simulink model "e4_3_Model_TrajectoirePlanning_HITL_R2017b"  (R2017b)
settings: Solver=FixedStepAuto  StartTime=0.0  StopTime=inf  FixedStep=sampleTime  RelTol=1e-3  EnableMultiTasking=on
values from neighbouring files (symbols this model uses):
  k2_d_x = 1/2    (= 0.5)    [e4_3_Model_TrajectoirePlanning_code.m]    (also in e4_1_Model_TrajectoirePlanning_HITL_code.m; e4_1_TF_TrajectoirePlanning_code.m = 1; e4_1_Model_TrajectoirePlanning_code.m; e4_2_TF_TrajectoirePlanning_code.m = 1)
  k2_d_y = 1/2.65    (= 0.377358490566)    [e4_3_Model_TrajectoirePlanning_code.m]    (also in e4_1_Model_TrajectoirePlanning_HITL_code.m; e4_1_TF_TrajectoirePlanning_code.m = 1; e4_1_Model_TrajectoirePlanning_code.m; e4_2_TF_TrajectoirePlanning_code.m = 1)
  k2_d_z = 10    [e4_3_Model_TrajectoirePlanning_code.m]    (also in e4_1_Model_TrajectoirePlanning_HITL_code.m; e4_1_TF_TrajectoirePlanning_code.m; e4_1_Model_TrajectoirePlanning_code.m; e4_2_TF_TrajectoirePlanning_code.m)
  k2_p_x = 1/1.55    (= 0.645161290323)    [e4_3_Model_TrajectoirePlanning_code.m]    (also in e4_1_Model_TrajectoirePlanning_HITL_code.m; e4_1_TF_TrajectoirePlanning_code.m = 1.25; e4_1_Model_TrajectoirePlanning_code.m; e4_2_TF_TrajectoirePlanning_code.m = 1.25)
  k2_p_y = 1/2.5    (= 0.4)    [e4_3_Model_TrajectoirePlanning_code.m]    (also in e4_1_Model_TrajectoirePlanning_HITL_code.m; e4_1_TF_TrajectoirePlanning_code.m = 1.25; e4_1_Model_TrajectoirePlanning_code.m; e4_2_TF_TrajectoirePlanning_code.m = 1.25)
  k2_p_yaw = 1.6    [e4_3_Model_TrajectoirePlanning_code.m]    (also in e4_1_Model_TrajectoirePlanning_HITL_code.m; e4_1_TF_TrajectoirePlanning_code.m; e4_1_Model_TrajectoirePlanning_code.m; e4_2_TF_TrajectoirePlanning_code.m)
  k2_p_z = 1    [e4_3_Model_TrajectoirePlanning_code.m]    (also in e4_1_Model_TrajectoirePlanning_HITL_code.m; e4_1_TF_TrajectoirePlanning_code.m; e4_1_Model_TrajectoirePlanning_code.m; e4_2_TF_TrajectoirePlanning_code.m)
  sampleTime = 0.01    [startSimulation.m]    (also in start.m)
  saturation_psi = 2    [startSimulation.m]    (also in start.m)
  saturation_x = 2    [startSimulation.m]    (also in start.m)
  saturation_y = 2    [startSimulation.m]    (also in start.m)
  saturation_z = 2    [startSimulation.m]    (also in start.m)
libraries: simulink x3, etargetslib x2, aerolibanimutils x1

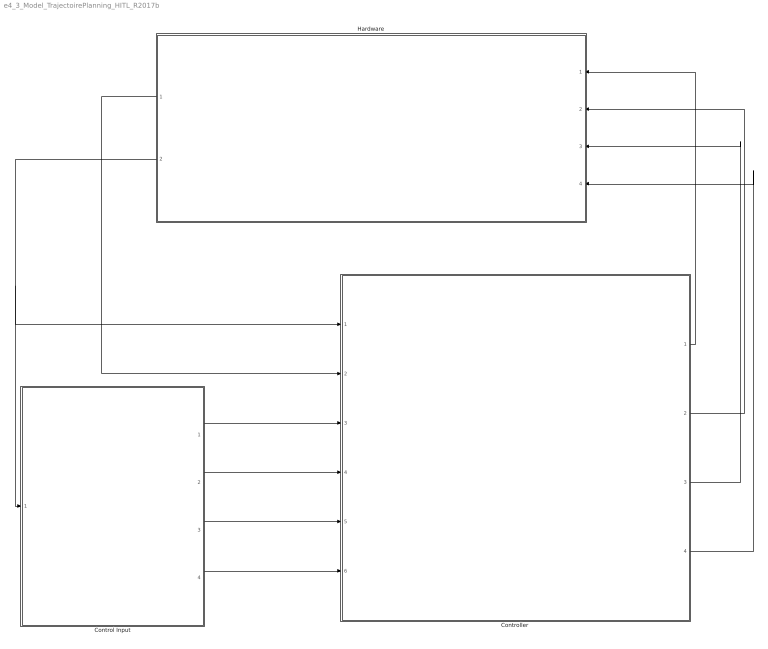
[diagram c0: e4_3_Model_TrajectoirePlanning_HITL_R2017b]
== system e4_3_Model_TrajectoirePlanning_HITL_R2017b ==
  Control Input : Subsystem
  "Controller " : Subsystem
  Hardware : Subsystem
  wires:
  Control Input/1(ux) -> "Controller "/3(Control input X)
  Control Input/2(uy) -> "Controller "/4(Control input Y)
  Control Input/3(uz) -> "Controller "/5(Control input H)
  Control Input/4(upsi) -> "Controller "/6(Control input Psi)
  "Controller "/1(Controller Output X) -> Hardware/1(X)
  "Controller "/2(Controller Output Y) -> Hardware/2(Y)
  "Controller "/3(Controller Output H) -> Hardware/3(H)
  "Controller "/4(Controller Output Psi) -> Hardware/4(Psi)
  Hardware/1(Vel) -> "Controller "/2(Feedback Velocity)
  Hardware/2(Pos) -> "Controller "/1(Feedback Position), Control Input/1(Position Feedback)

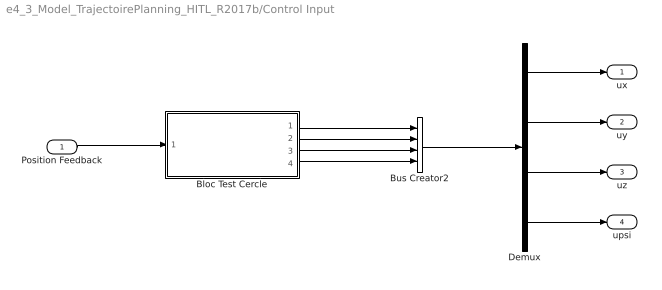
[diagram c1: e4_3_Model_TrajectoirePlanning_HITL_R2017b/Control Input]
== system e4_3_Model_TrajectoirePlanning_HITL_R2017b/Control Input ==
  Position Feedback : Inport
  Bloc Test Cercle : Subsystem
  Bus Creator2 : BusCreator  Inputs=4
  Demux : Demux
  ux : Outport
  uy : Outport  Port=2
  uz : Outport  Port=3
  upsi : Outport  Port=4
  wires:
  Demux/2 -> uy/1
  Demux/1 -> ux/1
  Demux/3 -> uz/1
  Demux/4 -> upsi/1
  Bloc Test Cercle/2(uy) -> Bus Creator2/2
  Bloc Test Cercle/4(upsi) -> Bus Creator2/4
  Position Feedback/1 -> Bloc Test Cercle/1(Position Feedback)
  Bloc Test Cercle/3(uz) -> Bus Creator2/3
  Bus Creator2/1 -> Demux/1
  Bloc Test Cercle/1(ux) -> Bus Creator2/1

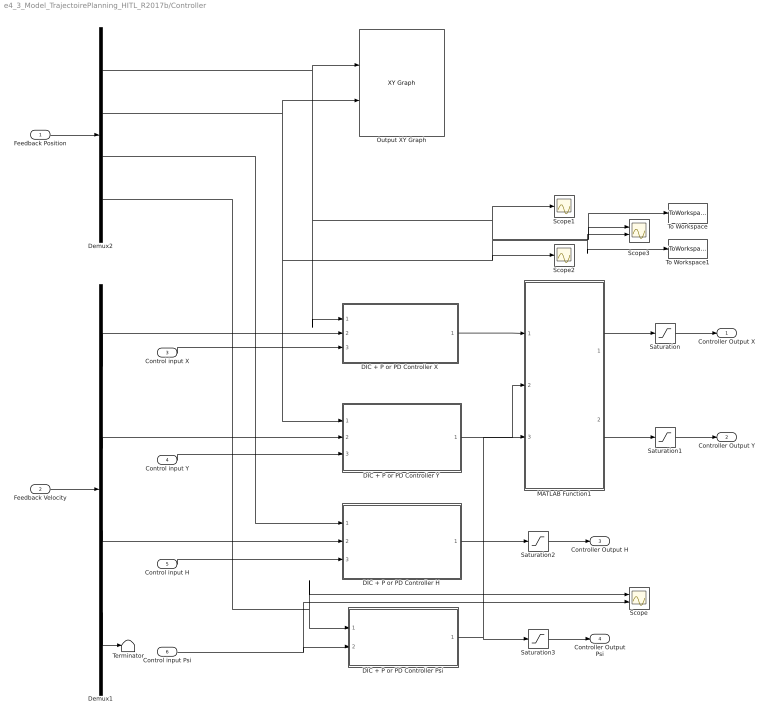
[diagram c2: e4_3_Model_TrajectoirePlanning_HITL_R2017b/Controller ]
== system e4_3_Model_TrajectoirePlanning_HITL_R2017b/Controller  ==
  Feedback Position : Inport
  Feedback Velocity : Inport  Port=2
  Control input X : Inport  Port=3
  Control input Y : Inport  Port=4
  Control input H : Inport  Port=5
  Control input Psi : Inport  Port=6
  DIC + P or PD Controller H : Subsystem
  DIC + P or PD Controller Psi : Subsystem
  DIC + P or PD Controller X : Subsystem
  DIC + P or PD Controller Y : Subsystem
  Demux1 : Demux
  Demux2 : Demux
  MATLAB Function1 : MATLAB Function  TreatAsAtomicUnit=on
  Output XY Graph : simulink/Sinks/XY Graph  xmin=-3  xmax=3  ymin=-3  ymax=3  st=-1
  Saturation : Saturate  UpperLimit=saturation_x  LowerLimit=-saturation_x
  Saturation1 : Saturate  UpperLimit=saturation_y  LowerLimit=-saturation_y
  Saturation2 : Saturate  UpperLimit=saturation_z  LowerLimit=-saturation_z
  Saturation3 : Saturate  UpperLimit=saturation_psi  LowerLimit=-saturation_psi
  Scope : Scope  NumInputPorts=2
  Scope1 : Scope
  Scope2 : Scope
  Scope3 : Scope  NumInputPorts=2
  Terminator : Terminator
  To Workspace : ToWorkspace  VariableName=x_desire  SampleTime=-1
  To Workspace1 : ToWorkspace  VariableName=y_desire  SampleTime=-1
  Controller Output X : Outport
  Controller Output Y : Outport  Port=2
  Controller Output H : Outport  Port=3
  Controller Output Psi : Outport  Port=4
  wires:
  Feedback Position/1 -> Demux2/1
  Feedback Velocity/1 -> Demux1/1
  Demux1/2 -> DIC + P or PD Controller Y/2(Feedback Velocity Y)
  Demux2/3 -> DIC + P or PD Controller H/1(Feedback Position H)
  Demux1/1 -> DIC + P or PD Controller X/2(Feedback Velocity X)
  Demux1/3 -> DIC + P or PD Controller H/2(Feedback Velocity H)
  Control input X/1 -> DIC + P or PD Controller X/3(Control Input X)
  Control input Psi/1 -> Scope/2, DIC + P or PD Controller Psi/2(Control input Psi)
  Control input H/1 -> DIC + P or PD Controller H/3(Control Input H)
  Saturation/1 -> Controller Output X/1
  Saturation1/1 -> Controller Output Y/1
  Saturation2/1 -> Controller Output H/1
  Saturation3/1 -> Controller Output Psi/1
  Control input Y/1 -> DIC + P or PD Controller Y/3(Control Input Y)
  DIC + P or PD Controller H/1(Controller Output H) -> Saturation2/1
  DIC + P or PD Controller Psi/1(Controller Output Psi) -> MATLAB Function1/3(psi), Saturation3/1
  Demux2/4 -> Scope/1, DIC + P or PD Controller Psi/1(Feedback Position Psi)
  Demux1/4 -> Terminator/1
  DIC + P or PD Controller Y/1(Controller Output Y) -> MATLAB Function1/2(eay)
  MATLAB Function1/2(y) -> Saturation1/1
  MATLAB Function1/1(x) -> Saturation/1
  DIC + P or PD Controller X/1(Controller Output X) -> MATLAB Function1/1(eax)
  Demux2/1 -> DIC + P or PD Controller X/1(Feedback Position X), Scope3/1, To Workspace/1, Scope1/1, Output XY Graph/1
  Demux2/2 -> DIC + P or PD Controller Y/1(Feedback Position Y), Scope3/2, To Workspace1/1, Scope2/1, Output XY Graph/2

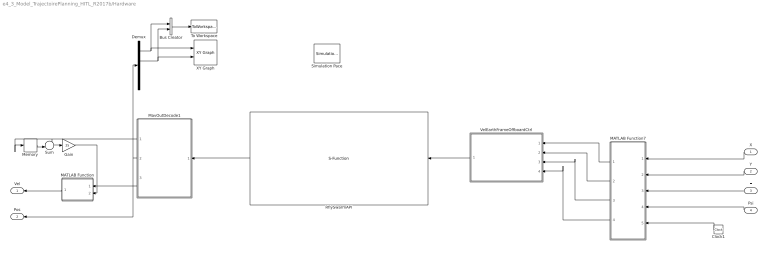
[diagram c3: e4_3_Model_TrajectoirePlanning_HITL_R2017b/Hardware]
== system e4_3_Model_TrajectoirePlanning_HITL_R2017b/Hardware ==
  X : Inport
  Y : Inport  Port=2
  H : Inport  Port=3
  Psi : Inport  Port=4
  Bus Creator : BusCreator  Inputs=2
  Clock1 : Clock
  Demux : Demux
  Gain : Gain  Gain=25
  MATLAB Function : MATLAB Function  TreatAsAtomicUnit=on
  MATLAB Function7 : MATLAB Function  TreatAsAtomicUnit=on
  MavOutDecode1 : MATLAB Function  TreatAsAtomicUnit=on
  Memory : Memory
  RflySwarmAPI : S-Function  FunctionName=RflyUdpFast  Parameters=port,num,modeValue,T,ip  SFunctionDeploymentMode=off  EnableBusSupport=off  mask(UDP Receive){ip=255.255.255.255, port=20100, num=1, mode=FullData Mode, T=1/25, modeValue=0}
      mask prompts: ip "UDP IP Address"; port "UDP Port"; num "vehicle Number"; mode "UDP Mode"; T "Sample Time"
      mask help: This block receives bytes from an UDP/IP connection. The first parameter is the UDP port on the first CopterSim App The second parameter is the total vehicle number The third parameter is the data mode. check the help button for the definition
      mask init:
      | if strcmp(mode,'FullData Mode')
      |     modeValue = 0;
      | elseif strcmp(mode,'SimpleData Mode') 
      |     modeValue = 1;
      | elseif strcmp(mode,'UltraSimple Mode') 
      |     modeValue = 2;
      | else
      |     modeValue = 0;
      | end
  Simulation Pace : aerolibanimutils/Simulation Pace  SimulationPace=1  SleepMode=MATLAB Thread  OutputPaceError=off  SampleTime=-1
  Sum : Sum  Inputs=+-|
  To Workspace : ToWorkspace  VariableName=Pos1  SaveFormat=Timeseries  SampleTime=-1
  VelEarthFrameOffboardCtrl : Subsystem
  XY Graph : simulink/Sinks/XY Graph  Commented=on  xmin=-1  xmax=1  ymin=-1  ymax=1  st=-1
  Vel : Outport
  Pos : Outport  Port=2
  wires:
  Gain/1 -> MATLAB Function/2(psi)
  Demux/2 -> Bus Creator/2, XY Graph/2
  Demux/1 -> Bus Creator/1, XY Graph/1
  Sum/1 -> Gain/1
  X/1 -> MATLAB Function7/1(X)
  MATLAB Function7/2(y1) -> VelEarthFrameOffboardCtrl/2(VeY_ms)
  MATLAB Function7/3(h1) -> VelEarthFrameOffboardCtrl/3(VeZ_ms)
  MATLAB Function7/1(x1) -> VelEarthFrameOffboardCtrl/1(VeX_ms)
  Clock1/1 -> MATLAB Function7/5(t)
  MavOutDecode1/2(localPos) -> Pos/1, Demux/1
  Memory/1 -> Sum/2
  MavOutDecode1/1(Psi) -> Memory/1, Sum/1
  RflySwarmAPI/1 -> MavOutDecode1/1(u)
  VelEarthFrameOffboardCtrl/1(Out1) -> RflySwarmAPI/1
  Bus Creator/1 -> To Workspace/1
  MavOutDecode1/3(localVel) -> MATLAB Function/1(v)
  MATLAB Function7/4(p1) -> VelEarthFrameOffboardCtrl/4(yawRate_rads)
  Y/1 -> MATLAB Function7/2(Y)
  H/1 -> MATLAB Function7/3(H)
  Psi/1 -> MATLAB Function7/4(Psi)
  MATLAB Function/1(y) -> Vel/1

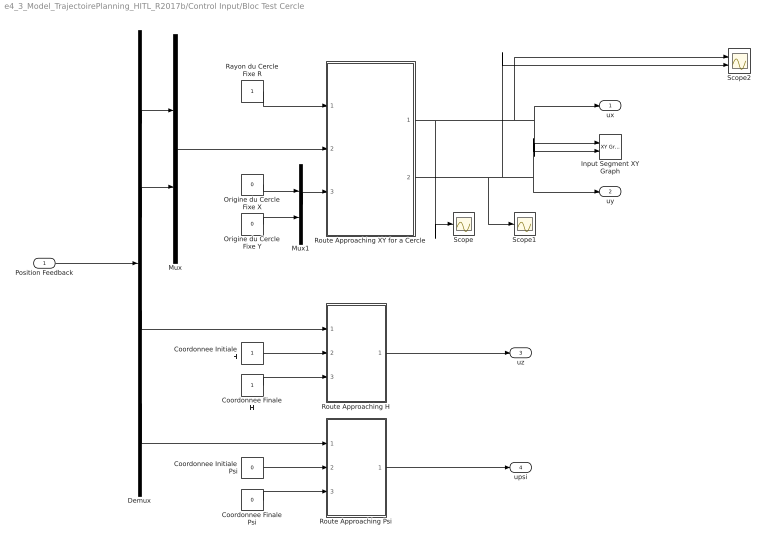
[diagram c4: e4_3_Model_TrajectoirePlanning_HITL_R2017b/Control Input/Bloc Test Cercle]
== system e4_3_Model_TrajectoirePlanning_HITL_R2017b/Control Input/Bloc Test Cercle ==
  Position Feedback : Inport
  Coordonnee Finale H : Constant
  Coordonnee Finale Psi : Constant  Value=0
  Coordonnee Initiale H : Constant
  Coordonnee Initiale Psi : Constant  Value=0
  Demux : Demux
  Input Segment XY Graph : simulink/Sinks/XY Graph  xmin=-10  xmax=10  ymin=-10  ymax=10  st=-1
  Mux : Mux  Inputs=2
  Mux1 : Mux  Inputs=2
  Origine du Cercle Fixe X : Constant  Value=0
  Origine du Cercle Fixe Y : Constant  Value=0
  Rayon du Cercle Fixe R : Constant
  Route Approaching H : MATLAB Function  TreatAsAtomicUnit=on  SystemSampleTime=sampleTime
  Route Approaching Psi : MATLAB Function  TreatAsAtomicUnit=on  SystemSampleTime=sampleTime
  Route Approaching XY for a Cercle : MATLAB Function  TreatAsAtomicUnit=on  SystemSampleTime=sampleTime
  Scope : Scope
  Scope1 : Scope
  Scope2 : Scope  NumInputPorts=2
  ux : Outport
  uy : Outport  Port=2
  uz : Outport  Port=3
  upsi : Outport  Port=4
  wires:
  Position Feedback/1 -> Demux/1
  Coordonnee Finale H/1 -> Route Approaching H/3(P_final)
  Coordonnee Finale Psi/1 -> Route Approaching Psi/3(P_final)
  Coordonnee Initiale Psi/1 -> Route Approaching Psi/2(P_init)
  Route Approaching H/1(P_d) -> uz/1
  Route Approaching Psi/1(P_d) -> upsi/1
  Demux/3 -> Route Approaching H/1(P_feedback)
  Demux/2 -> Mux/2
  Demux/4 -> Route Approaching Psi/1(P_feedback)
  Coordonnee Initiale H/1 -> Route Approaching H/2(P_init)
  Demux/1 -> Mux/1
  Mux/1 -> Route Approaching XY for a Cercle/2(P_feedback)
  Rayon du Cercle Fixe R/1 -> Route Approaching XY for a Cercle/1(P_Rayon)
  Mux1/1 -> Route Approaching XY for a Cercle/3(P_Origine)
  Origine du Cercle Fixe X/1 -> Mux1/1
  Origine du Cercle Fixe Y/1 -> Mux1/2
  Route Approaching XY for a Cercle/2(P_dy) -> Scope2/2, uy/1, Input Segment XY Graph/2, Scope1/1
  Route Approaching XY for a Cercle/1(P_dx) -> Scope2/1, ux/1, Input Segment XY Graph/1, Scope/1

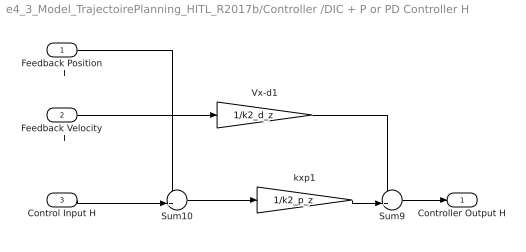
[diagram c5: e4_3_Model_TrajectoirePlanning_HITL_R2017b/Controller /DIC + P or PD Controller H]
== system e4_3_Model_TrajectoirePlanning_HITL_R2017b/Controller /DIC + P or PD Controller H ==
  Feedback Position H : Inport
  Feedback Velocity H : Inport  Port=2
  Control Input H : Inport  Port=3
  Sum10 : Sum  Inputs=-+|
  Sum9 : Sum  Inputs=-+|
  Vx-d1 : Gain  Gain=1/k2_d_z
  kxp1 : Gain  Gain=1/k2_p_z
  Controller Output H : Outport
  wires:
  Sum9/1 -> Controller Output H/1
  Feedback Velocity H/1 -> Vx-d1/1
  Sum10/1 -> kxp1/1
  kxp1/1 -> Sum9/2
  Vx-d1/1 -> Sum9/1
  Control Input H/1 -> Sum10/2
  Feedback Position H/1 -> Sum10/1

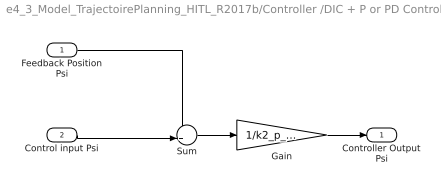
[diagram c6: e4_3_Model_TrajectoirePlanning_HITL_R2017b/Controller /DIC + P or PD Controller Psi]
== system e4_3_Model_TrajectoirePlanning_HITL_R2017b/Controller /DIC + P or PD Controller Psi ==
  Feedback Position Psi : Inport
  Control input Psi : Inport  Port=2
  Gain : Gain  Gain=1/k2_p_yaw
  Sum : Sum  Inputs=-+|
  Controller Output Psi : Outport
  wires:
  Gain/1 -> Controller Output Psi/1
  Sum/1 -> Gain/1
  Control input Psi/1 -> Sum/2
  Feedback Position Psi/1 -> Sum/1

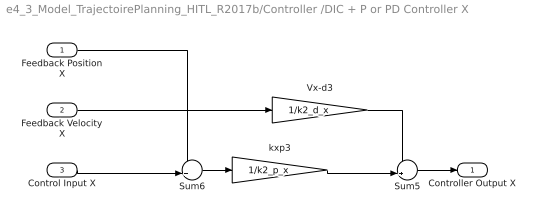
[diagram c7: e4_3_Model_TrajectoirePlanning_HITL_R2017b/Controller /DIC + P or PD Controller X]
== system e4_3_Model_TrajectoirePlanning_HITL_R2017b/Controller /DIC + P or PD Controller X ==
  Feedback Position X : Inport
  Feedback Velocity X : Inport  Port=2
  Control Input X : Inport  Port=3
  Sum5 : Sum  Inputs=-+|
  Sum6 : Sum  Inputs=-+|
  Vx-d3 : Gain  Gain=1/k2_d_x
  kxp3 : Gain  Gain=1/k2_p_x
  Controller Output X : Outport
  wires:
  Vx-d3/1 -> Sum5/1
  kxp3/1 -> Sum5/2
  Sum5/1 -> Controller Output X/1
  Sum6/1 -> kxp3/1
  Control Input X/1 -> Sum6/2
  Feedback Velocity X/1 -> Vx-d3/1
  Feedback Position X/1 -> Sum6/1

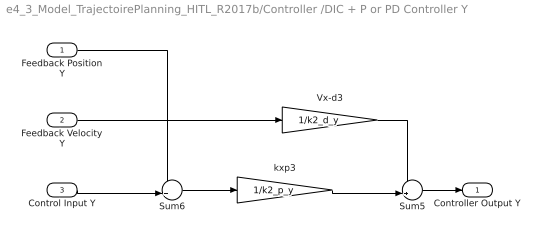
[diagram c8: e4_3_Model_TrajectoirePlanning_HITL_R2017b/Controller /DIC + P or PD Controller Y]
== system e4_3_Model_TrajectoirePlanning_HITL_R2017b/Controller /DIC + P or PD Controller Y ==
  Feedback Position Y : Inport
  Feedback Velocity Y : Inport  Port=2
  Control Input Y : Inport  Port=3
  Sum5 : Sum  Inputs=-+|
  Sum6 : Sum  Inputs=-+|
  Vx-d3 : Gain  Gain=1/k2_d_y
  kxp3 : Gain  Gain=1/k2_p_y
  Controller Output Y : Outport
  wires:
  Feedback Velocity Y/1 -> Vx-d3/1
  Feedback Position Y/1 -> Sum6/1
  Sum6/1 -> kxp3/1
  kxp3/1 -> Sum5/2
  Vx-d3/1 -> Sum5/1
  Sum5/1 -> Controller Output Y/1
  Control Input Y/1 -> Sum6/2

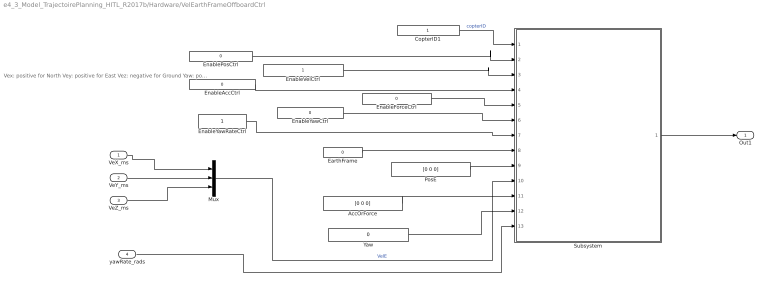
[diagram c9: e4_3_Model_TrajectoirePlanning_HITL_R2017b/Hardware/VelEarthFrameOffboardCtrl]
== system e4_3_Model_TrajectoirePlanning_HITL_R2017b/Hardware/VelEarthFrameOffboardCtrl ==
  note: Vex: positive for North Vey: positive for East Vez: negative for Ground Yaw: positive for right rotation
  VeX_ms : Inport
  VeY_ms : Inport  Port=2
  VeZ_ms : Inport  Port=3
  yawRate_rads : Inport  Port=4  PortDimensions=1
  AccOrForce : Constant  Value=[0 0 0]
  CopterID1 : Constant
  EarthFrame : Constant  Value=0
  EnableAccCtrl : Constant  Value=0
  EnableForceCtrl : Constant  Value=0
  EnablePosCtrl : Constant  Value=0
  EnableVelCtrl : Constant
  EnableYawCtrl : Constant  Value=0
  EnableYawRateCtrl : Constant
  Mux : Mux  Inputs=3
  PosE : Constant  Value=[0 0 0]
  Subsystem : Subsystem
  Yaw : Constant  Value=0
  Out1 : Outport  VectorParamsAs1DForOutWhenUnconnected=on
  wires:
  Yaw/1 -> Subsystem/12(yaw)
  EnableYawRateCtrl/1 -> Subsystem/7(EnYawrate)
  EnableYawCtrl/1 -> Subsystem/6(enYaw)
  EnableAccCtrl/1 -> Subsystem/4(enAcc)
  Mux/1 -> Subsystem/10(vel)  "VelE"
  EarthFrame/1 -> Subsystem/8(FrameIndex)
  yawRate_rads/1 -> Subsystem/13(yawrate)
  AccOrForce/1 -> Subsystem/11(acc)
  EnableVelCtrl/1 -> Subsystem/3(enVel)
  EnableForceCtrl/1 -> Subsystem/5(enForce)
  CopterID1/1 -> Subsystem/1(CopterID)  "copterID"
  EnablePosCtrl/1 -> Subsystem/2(enPos)
  PosE/1 -> Subsystem/9(pos)
  VeY_ms/1 -> Mux/2
  VeX_ms/1 -> Mux/1
  VeZ_ms/1 -> Mux/3
  Subsystem/1(Out1) -> Out1/1

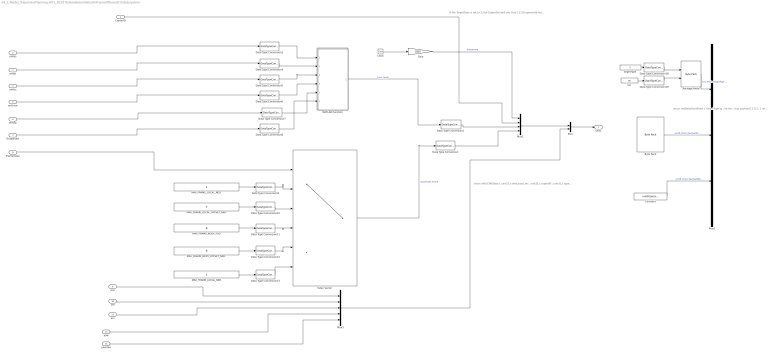
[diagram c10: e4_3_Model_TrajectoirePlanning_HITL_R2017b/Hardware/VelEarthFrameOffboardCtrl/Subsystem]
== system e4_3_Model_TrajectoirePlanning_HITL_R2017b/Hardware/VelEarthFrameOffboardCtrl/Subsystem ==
  note: struct netDataShortShort { TargetType tg ; int len ; char payload [ 112 ]; } netDataShortShort ;
  note: struct inHILCMDData { uint32_t time_boot_ms ; uint32_t copterID ; uint32_t type_mask ; uint32_t coordinate_frame ; float ctrls [ 11 ]; };
  note: If the TargetTpye is set to 3, the CopterSim will use Ctrs[1:11] to generate mavlink S ET_POSITION_TARGET_LOCAL_NED msg to UAV's Offboard mode Control， If the PX4 is not armed, CopterSim will send the arm command repeatly. If the PX4 is not in Offboard(Guided) Mode, CopterSim will send SET_MODE msg repeatly.
  CopterID : Inport
  enPos : Inport  Port=2
  enVel : Inport  Port=3
  enAcc : Inport  Port=4
  enForce : Inport  Port=5
  enYaw : Inport  Port=6
  EnYawrate : Inport  Port=7
  FrameIndex : Inport  Port=8
  pos : Inport  Port=9  PortDimensions=3
  vel : Inport  Port=10  PortDimensions=3
  acc : Inport  Port=11  PortDimensions=3
  yaw : Inport  Port=12  PortDimensions=1
  yawrate : Inport  Port=13  PortDimensions=1
  Byte Pack : etargetslib/Byte Pack  Commented=on  datatypes={'uint32','single'}  byteAlign=1
  Clock : Clock
  Constant : Constant  Commented=on  Value=uint8(zeros(32,1))
  Data Type Conversion : DataTypeConversion  OutDataTypeStr=double
  Data Type Conversion1 : DataTypeConversion  OutDataTypeStr=double
  Data Type Conversion{9..13} (5 alike) : DataTypeConversion  OutDataTypeStr=uint8
  Data Type Conversion18 : DataTypeConversion  Commented=on  OutDataTypeStr=uint32
  Data Type Conversion19 : DataTypeConversion  Commented=on  OutDataTypeStr=int32
  Data Type Conversion{3..8} (6 alike) : DataTypeConversion  OutDataTypeStr=boolean
  Gain : Gain  Gain=1000
  Index Vector : MultiPortSwitch  DataPortOrder=Zero-based contiguous  Inputs=5  zeroidx=on
  MATLAB Function : MATLAB Function  TreatAsAtomicUnit=on
  MAV_FRAME_BODY_FRD : Constant  Value=8
  "MAV_FRAME_BODY_OFFSET_NED " : Constant  Value=9
  MAV_FRAME_LOCAL_NED : Constant
  "MAV_FRAME_LOCAL_NED " : Constant
  MAV_FRAME_LOCAL_OFFSET_NED : Constant  Value=7
  Mux : Mux  Inputs=2
  Mux1 : Mux
  Mux2 : Mux  Commented=on  Inputs=3
  Mux5 : Mux  Inputs=5
  Package Head : etargetslib/Byte Pack  Commented=on  datatypes={'uint32','int32'}  byteAlign=4
  TargetType : Constant  Commented=on  Value=3  OutDataTypeStr=Inherit: Inherit via back propagation
  len : Constant  Commented=on  Value=80  OutDataTypeStr=Inherit: Inherit via back propagation
  Out1 : Outport  VectorParamsAs1DForOutWhenUnconnected=on
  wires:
  Data Type Conversion7/1 -> MATLAB Function/5(Yaw)
  Data Type Conversion6/1 -> MATLAB Function/4(Force)
  vel/1 -> Mux5/2
  MAV_FRAME_BODY_FRD/1 -> Data Type Conversion11/1
  Data Type Conversion3/1 -> MATLAB Function/1(pos)
  Data Type Conversion5/1 -> MATLAB Function/3(Acc)
  Data Type Conversion4/1 -> MATLAB Function/2(vel)
  Data Type Conversion8/1 -> MATLAB Function/6(Yawrate)
  enAcc/1 -> Data Type Conversion5/1
  enYaw/1 -> Data Type Conversion7/1
  EnYawrate/1 -> Data Type Conversion8/1
  enForce/1 -> Data Type Conversion6/1
  "MAV_FRAME_LOCAL_NED "/1 -> Data Type Conversion9/1
  enPos/1 -> Data Type Conversion3/1
  Data Type Conversion9/1 -> Index Vector/2
  Data Type Conversion10/1 -> Index Vector/3
  Index Vector/1 -> Data Type Conversion/1  "coordinate_frame"
  Constant/1 -> Mux2/3  "uint8 (char) Payload[80:111]"
  Data Type Conversion18/1 -> Package Head/1
  Clock/1 -> Gain/1
  len/1 -> Data Type Conversion19/1
  Mux5/1 -> Mux/2
  MATLAB Function/1(y) -> Data Type Conversion1/1  "type_mask"
  Package Head/1 -> Mux2/1  "int (int32) TargetType & len"
  TargetType/1 -> Data Type Conversion18/1
  Gain/1 -> Mux1/1  "timestamp"
  Data Type Conversion19/1 -> Package Head/2
  pos/1 -> Mux5/1
  Byte Pack/1 -> Mux2/2  "uint8 (char) Payload[0:79]"
  Data Type Conversion13/1 -> Index Vector/6
  Data Type Conversion12/1 -> Index Vector/5
  acc/1 -> Mux5/3
  FrameIndex/1 -> Index Vector/1
  MAV_FRAME_LOCAL_NED/1 -> Data Type Conversion13/1
  MAV_FRAME_LOCAL_OFFSET_NED/1 -> Data Type Conversion10/1
  Data Type Conversion11/1 -> Index Vector/4
  "MAV_FRAME_BODY_OFFSET_NED "/1 -> Data Type Conversion12/1
  enVel/1 -> Data Type Conversion4/1
  yaw/1 -> Mux5/4
  yawrate/1 -> Mux5/5
  CopterID/1 -> Mux1/2
  Mux1/1 -> Mux/1
  Mux/1 -> Out1/1
  Data Type Conversion/1 -> Mux1/4
  Data Type Conversion1/1 -> Mux1/3

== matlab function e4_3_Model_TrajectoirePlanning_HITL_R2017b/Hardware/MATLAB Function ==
function y = fcn(v,psi)

y = [v;psi];

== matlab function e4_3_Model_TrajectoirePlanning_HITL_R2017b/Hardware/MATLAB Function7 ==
function [x1,y1,h1,p1] = fcn(X,Y,H,Psi,t)

% position1=[u(1,1);u(3,1);0];
% position2=[u(2,1);u(4,1);0];
if t<5
    x1=0;
    y1=0;
    h1=-1;
    p1=0;
else
    x1=X;
    y1=Y;
    h1=-H;
    p1=Psi;
   
end

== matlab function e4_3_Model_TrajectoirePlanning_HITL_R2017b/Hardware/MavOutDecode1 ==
function [Psi,localPos,localVel] = fcn(u)
localPos = [u(7:8);-u(9);u(6)];
localVel = u(10:12);
Psi=u(6);

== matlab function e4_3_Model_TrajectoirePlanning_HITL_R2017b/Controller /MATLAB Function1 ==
function [x,y] = fcn(eax,eay,psi)
g=9.8;

theta =eax/g;% vx
phi =eay/g;% vy
R=[cos(psi),-sin(psi);
    sin(psi),cos(psi)];
u=R^(-1)*[theta;phi];
x=u(1);
y=u(2);

== matlab function e4_3_Model_TrajectoirePlanning_HITL_R2017b/Control Input/Bloc Test 
Cercle/Route Approaching H ==
function P_d = fcn(P_feedback, P_init, P_final)

% determine the constants
a0  = 10;

% the parameters of PD controller: 1/k2
% according to P287 of 《多旋翼飞行器设计与控制》,
% these two parameters should be equal? Is that true?

% global k2_p_z;
% global k2_d_z;
% k2_p_z=0.1;
% k2_d_z=0.1;

% the parameter of 'approaching'
k0_z=0.1;
k1_z=1;

persistent P_static;
if isempty(P_static)
    P_static=0; % the initilized value of position for giving a initial UAV position
end

P_static = P_feedback;

% the iterative process
P_perp = P_final+(P_init-P_final)*((P_static-P_final)'*(P_init-P_final))/(norm(P_final-P_init + 0.000001))^2;
% this extra '+ 0.000001' is for avoiding that 
% the zero denominator turns to zero.
temp  = satgd(k0_z*(P_final - P_static)+k1_z*(P_perp-P_static),a0);
P_d = P_static + temp;

== matlab function e4_3_Model_TrajectoirePlanning_HITL_R2017b/Control Input/Bloc Test 
Cercle/Route Approaching Psi ==
function P_d = fcn(P_feedback, P_init, P_final)

% determine the constants
a0  = 10;

% the parameters of PD controller: 1/k2
% according to P287 of 《多旋翼飞行器设计与控制》,
% these two parameters should be equal? Is that true?

% global k2_p_yaw;
% global k2_d_yaw;
% k2_p_yaw=0.1;
% k2_d_yaw=0.1;

% the parameter of 'approaching'
k0_yaw=0.1;
k1_yaw=1;

persistent P_static;
if isempty(P_static)
    P_static=0; % the initilized value of position for giving a initial UAV position
end

P_static = P_feedback;

% the iterative process
P_perp = P_final+(P_init-P_final)*((P_static-P_final)'*(P_init-P_final))/(norm(P_final-P_init + 0.000001))^2;
% this extra '+ 0.000001' is for avoiding that 
% the zero denominator turns to zero.
temp  = satgd(k0_yaw*(P_final - P_static)+k1_yaw*(P_perp-P_static),a0);
P_d = P_static + temp;

== matlab function e4_3_Model_TrajectoirePlanning_HITL_R2017b/Control Input/Bloc Test 
Cercle/Route Approaching XY for a Cercle ==
function [P_dx,P_dy] = fcn(P_Rayon, P_feedback, P_Origine)

% determine the constants
a0  = 10;

% the parameters of PD controller: 1/k2
% according to P287 of 《多旋翼飞行器设计与控制》,
% these two parameters should be equal? Is that true?

% global k2_p_x;
% global k2_d_x;
% k2_p_x=0.1;
% k2_d_x=0.1;

% the parameter of 'approaching'
% k0_x=0.3;
% k1_x=0.3;
% k0_x=0.3;
% k1_x=0.7;
k0_x=0.3;
k1_x=1;

% Determine the navagation points for a cercle, four for the condition
% Point_1=[P_Origine(1)-P_Rayon;P_Origine(2)];
% Point_2=[P_Origine(1);P_Origine(2)+P_Rayon];
% Point_3=[P_Origine(1)+P_Rayon;P_Origine(2)];
% Point_4=[P_Origine(1);P_Origine(2)-P_Rayon];
% Point=[Point_1,Point_2,Point_3,Point_4];
% P_init=[0;0]; % the initialized position of UAV
% Distance=sqrt((Point(1,:)-P_init(1)).^2+(Point(2,:)-P_init(2)).^2);
% JL_data = [Point;Distance];
% [d,indice]=sort(JL_data(3,:));
% Point_start=Point(:,indice(1));

P_init=[0;0]; % the initialized position of UAV
persistent P_static;
if isempty(P_static)
    P_static=P_init; % the initilized value of position for giving a initial UAV position
end
P_static = P_feedback; % Except the initialization, the following position is gotten by the feedback 

% the iterative process
P_perp_rayon = P_Origine+(P_static-P_Origine)*(P_Rayon/(norm((P_static-P_Origine)+ 0.000001)));
% this extra '+ 0.000001' is for avoiding that 
% the zero denominator turns to zero.

%{

% this is a useless demo for 
% the itrative loop "Point_1 to Point_2 to Point_3 to Point_4 to Point_1" 
% i=indice(1);
% temp  = satgd(k0_x*(Point_start - P_static)+k1_x*(P_perp_rayon-P_static),a0);
% % while(true) 
%     if(norm(Point(:,i)-P_static)<=0.5)
%         if ((i+1)<=4)
% %             temp  = satgd(k0_x*(Point(:,i+1) - P_static)+k1_x*(P_perp_rayon-P_static),a0);       
%             i=i+1;
%         else
% %             temp  = satgd(k0_x*(Point(:,1) - P_static)+k1_x*(P_perp_rayon-P_static),a0);       
%             i=1;
%         end       
%     end
%     temp  = satgd(k0_x*(Point(:,i) - P_static)+k1_x*(P_perp_rayon-P_static),a0);
% end

%}
% A = [0,1;-1,0]*(((P_perp_rayon - P_static)+0.000001)/(norm((P_perp_rayon - P_static))+0.000001));
A = [0,1;-1,0]*(((P_Origine- P_static)+0.000001)/(norm((P_Origine - P_static))+0.000001));
temp  = satgd(k0_x*A+k1_x*(P_perp_rayon-P_static),a0);
P_d0 =P_static+temp;
P_dx=P_d0(1);
P_dy=P_d0(2);

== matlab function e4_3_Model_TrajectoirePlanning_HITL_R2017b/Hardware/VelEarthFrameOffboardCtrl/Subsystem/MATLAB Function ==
function y = fcn(pos,vel,Acc,Force,Yaw,Yawrate)
y=uint32(0);
if ~pos
    y = bitor(y,uint32(7));
end

if~vel
    y = bitor(y,bitshift(uint32(7),3));
end

if ~Acc
    y = bitor(y,bitshift(uint32(7),6));
end

if Force
    y = bitor(y,bitshift(uint32(1),9));
end

if ~Yaw
    y = bitor(y,bitshift(uint32(1),10));
end

if ~Yawrate
    y = bitor(y,bitshift(uint32(1),11));
end
